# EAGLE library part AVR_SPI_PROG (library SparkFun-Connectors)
AVR 10-pin ICSP Header This is the standard AVR In Circuit Serial Programming header. Minimal, but includes pin one indicator. Works with standard Olimex programmers. Also look for the 6-pin reduced version. Spark Fun Electronics SKU: PRT-00778

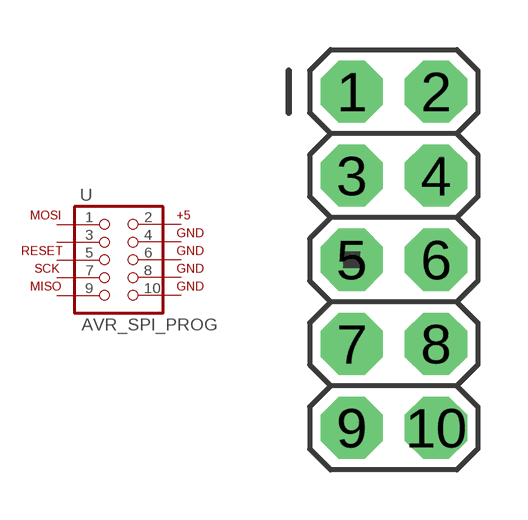
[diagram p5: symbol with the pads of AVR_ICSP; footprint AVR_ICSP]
Designator prefix -

## AVR_SPI_PROG  [AVR_ICSP]
1  1  pas
2  2  pas
3  3  pas
4  4  pas
5  5  pas
6  6  pas
7  7  pas
8  8  pas
9  9  pas
10  10  pas

## Footprint AVR_ICSP (pad centres in mm)
PIN HEADER
drill 1.016 pad 1.88 octagon: 1 -1.27,5.08; 2 1.27,5.08; 3 -1.27,2.54; 4 1.27,2.54; 5 -1.27,0; 6 1.27,0; 7 -1.27,-2.54; 8 1.27,-2.54; 9 -1.27,-5.08; 10 1.27,-5.08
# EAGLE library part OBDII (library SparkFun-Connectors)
OBDII connector footprint

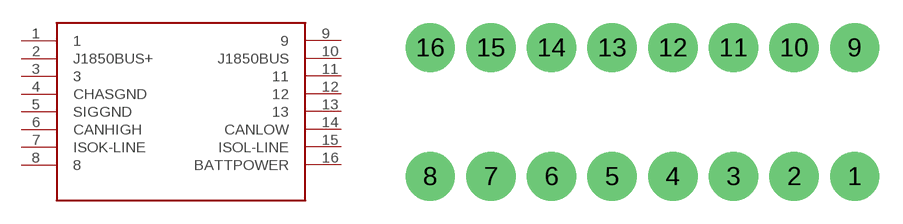
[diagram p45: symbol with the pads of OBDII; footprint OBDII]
Designator prefix -

## OBDII  [OBDII]
1  1
2  J1850BUS+
3  3
4  CHASGND
5  SIGGND
6  CANHIGH
7  ISOK-LINE
8  8
9  9
10  J1850BUS
11  11
12  12
13  13
14  CANLOW
15  ISOL-LINE
16  BATTPOWER

## Footprint OBDII (pad centres in mm)
OBDII Connector footprint, for your late model automotive needs
drill 2.2: 1 13.68,-3.81; 2 9.73,-3.81; 3 5.78,-3.81; 4 1.83,-3.81; 5 -2.12,-3.81; 6 -6.07,-3.81; 7 -10.02,-3.81; 8 -13.97,-3.81; 9 13.68,4.59; 10 9.73,4.59; 11 5.78,4.59; 12 1.83,4.59; 13 -2.12,4.59; 14 -6.07,4.59; 15 -10.02,4.59; 16 -13.97,4.59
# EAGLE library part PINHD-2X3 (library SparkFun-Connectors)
PIN HEADER

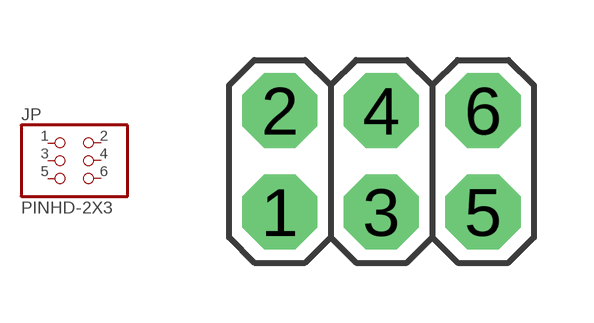
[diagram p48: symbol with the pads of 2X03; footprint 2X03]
Designator prefix JP

## PINHD-2X3  [2X03]
1  1  pas
2  2  pas
3  3  pas
4  4  pas
5  5  pas
6  6  pas

## Footprint 2X03 (pad centres in mm)
PIN HEADER
drill 1.016 pad 1.88 octagon: 1 -2.54,-1.27; 2 -2.54,1.27; 3 0,-1.27; 4 0,1.27; 5 2.54,-1.27; 6 2.54,1.27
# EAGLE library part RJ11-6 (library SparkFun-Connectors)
RJ11 Jack Simple 6 pin RJ11 jack. Commonly found on CAT3 devices and Microchip programmers. SKU: PRT-00132

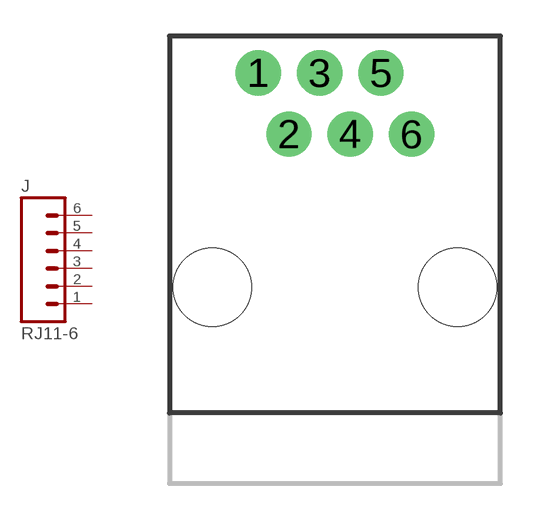
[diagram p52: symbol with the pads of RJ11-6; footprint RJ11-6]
Designator prefix J

## RJ11-6PTH  [RJ11-6]
1  1  pas
2  2  pas
3  3  pas
4  4  pas
5  5  pas
6  6  pas

## Footprint RJ11-6 (pad centres in mm)
drill 1.016 pad 1.88: 1 1.905,8.89; 2 3.175,6.35; 3 4.445,8.89; 4 5.715,6.35; 5 6.985,8.89; 6 8.255,6.35
hole 3.251 at 0,0
hole 3.251 at 10.16,0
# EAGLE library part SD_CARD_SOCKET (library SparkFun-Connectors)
SD/MMC Socket Media socket for SD and MMC cards. Push-push type. Schematic element and footprint production proven. Spark Fun Electronics SKU : PRT-00136

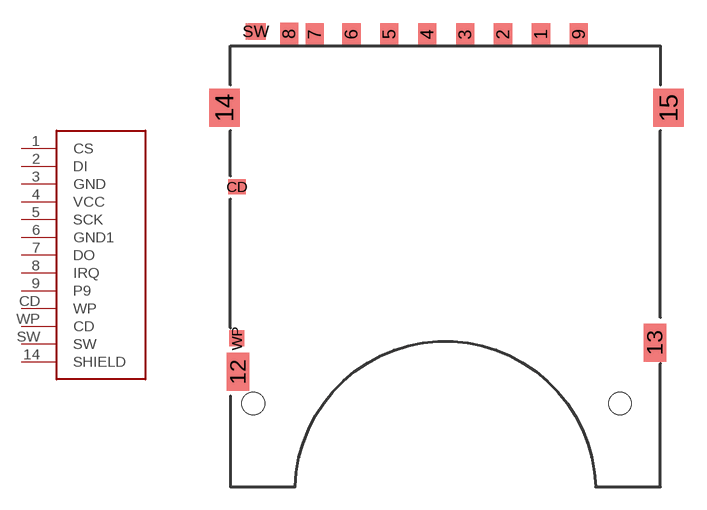
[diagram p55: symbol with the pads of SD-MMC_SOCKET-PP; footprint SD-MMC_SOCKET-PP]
Designator prefix -

## SD_CARD_SOCKETSD  [SD-MMC_SOCKET-PP]
1  CS
2  DI
3  GND
4  VCC
5  SCK
6  GND1
7  DO
8  IRQ
9  P9
14  SHIELD
CD  WP
SW  SW
WP  CD

## Footprint SD-MMC_SOCKET-PP (pad centres in mm)
smd 1.2 x 1.5: 1 6.88,29.85; 2 4.38,29.85; 3 1.88,29.85; 4 -0.62,29.85; 5 -3.12,29.85; 6 -5.62,29.85; 7 -8.04,29.85; 8 -9.728,29.87; 9 9.38,29.85
smd 1.5 x 2.5: 12 -13.1,7.6; 13 14.402,9.525
smd 2 x 2.5: 14 -14,25; 15 15.3,25
smd 1.15 x 1: CD -13.18,19.8
smd 1.3 x 1.1: SW -11.938,30.048
smd 1 x 1.05: WP -13.18,9.8
hole 1.5 at -12.1,5.5
hole 1.5 at 12.1,5.5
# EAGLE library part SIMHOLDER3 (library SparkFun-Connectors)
Alternate SIM card socket

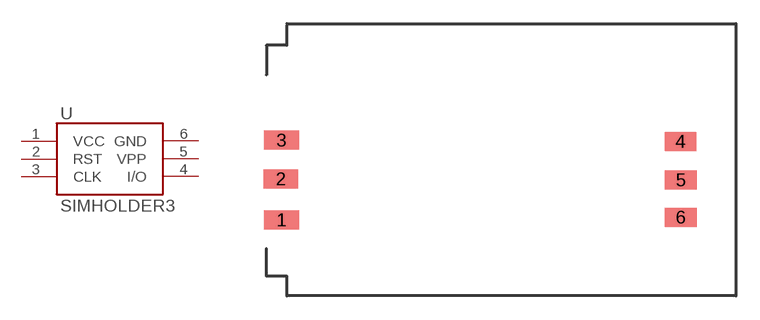
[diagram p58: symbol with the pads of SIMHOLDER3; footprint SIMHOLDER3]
Designator prefix -

## SIMHOLDER3  [SIMHOLDER3]
1  VCC
2  RST
3  CLK
4  I/O
5  VPP
6  GND

## Footprint SIMHOLDER3 (pad centres in mm)
smd 2.2 x 1.2: 1 0.95,4.81; 2 0.91,7.41; 3 0.95,9.86
smd 2 x 1.2: 4 26.2,9.78; 5 26.22,7.34; 6 26.22,4.98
